VERSION 5.8 ;
BUSBITCHARS "[]" ;
DIVIDERCHAR "/" ;
MANUFACTURINGGRID 0.05 ;

UNITS
    DATABASE MICRONS 1000 ;
END UNITS

SITE CoreSite
    CLASS CORE ;
    SIZE 5.400 BY 64.800 ;
END CoreSite

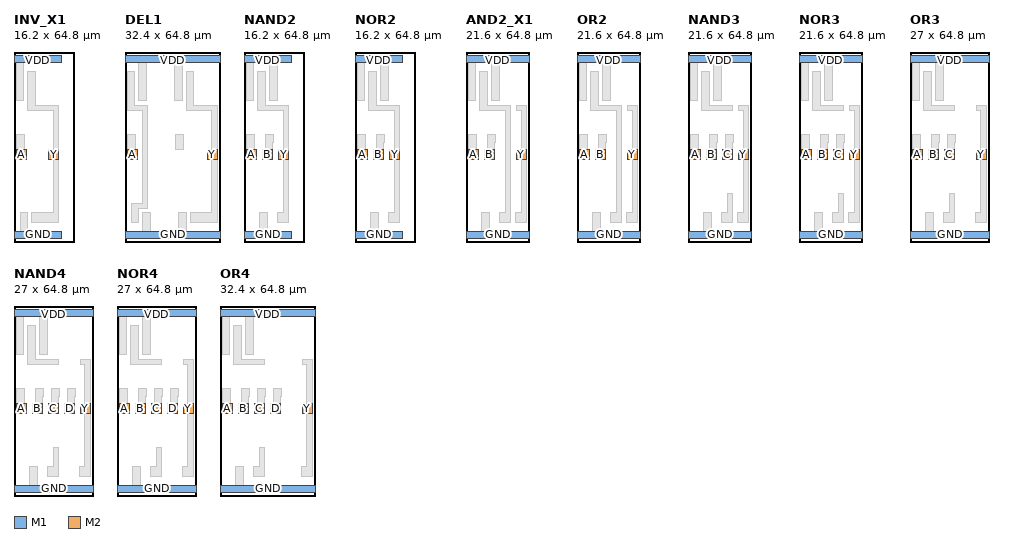
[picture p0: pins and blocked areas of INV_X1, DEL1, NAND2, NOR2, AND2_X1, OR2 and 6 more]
MACRO INV_X1
    CLASS CORE ;
    FOREIGN INV_X1 0.0 0.0 ;
    ORIGIN 0.0 0.0 ;
    SIZE 16.200 BY 64.800 ;
    SITE CoreSite ;

    PIN GND
        DIRECTION INOUT ;
        USE GROUND ;
        PORT
            LAYER M1 ;
                RECT 0.000 1.100 16.200 3.700 ;
        END
    END GND

    PIN VDD
        DIRECTION INOUT ;
        USE POWER ;
        PORT
            LAYER M1 ;
                RECT 0.000 61.100 16.200 63.700 ;
        END
    END VDD

    PIN A
        DIRECTION INPUT ;
        USE SIGNAL ;
        PORT
            LAYER M2 ;
                RECT 1.000 28.000 4.400 31.400 ;
        END
    END A

    PIN Y
        DIRECTION OUTPUT ;
        USE SIGNAL ;
        PORT
            LAYER M2 ;
                RECT 11.800 28.000 15.200 31.400 ;
        END
    END Y

    OBS
        LAYER M1 ;
            POLYGON 2.100 3.700  2.100 9.900  4.700 9.900  4.700 3.700 ;
            POLYGON 1.000 28.000  1.000 36.500  3.600 36.500  3.600 31.400  4.400 31.400  4.400 28.000 ;
            POLYGON 6.100 6.500  6.100 9.900  13.400 9.900  13.400 28.000  11.800 28.000  11.800 31.400  13.400 31.400  13.400 44.900  4.700 44.900  4.700 58.300  7.300 58.300  7.300 46.700  15.200 46.700  15.200 6.500 ;
            POLYGON 0.700 48.100  0.700 61.100  3.300 61.100  3.300 48.100 ;
    END

END INV_X1
MACRO DEL1
    CLASS CORE ;
    FOREIGN DEL1 0.0 0.0 ;
    ORIGIN 0.0 0.0 ;
    SIZE 32.400 BY 64.800 ;
    SITE CoreSite ;

    PIN GND
        DIRECTION INOUT ;
        USE GROUND ;
        PORT
            LAYER M1 ;
                RECT 0.000 1.100 32.400 3.700 ;
        END
    END GND

    PIN VDD
        DIRECTION INOUT ;
        USE POWER ;
        PORT
            LAYER M1 ;
                RECT 0.000 61.100 32.400 63.700 ;
        END
    END VDD

    PIN A
        DIRECTION INPUT ;
        USE SIGNAL ;
        PORT
            LAYER M2 ;
                RECT 1.000 28.000 4.400 31.400 ;
        END
    END A

    PIN Y
        DIRECTION OUTPUT ;
        USE SIGNAL ;
        PORT
            LAYER M2 ;
                RECT 28.000 28.000 31.400 31.400 ;
        END
    END Y

    OBS
        LAYER M1 ;
            POLYGON 6.100 3.700  6.100 9.900  8.700 9.900  8.700 3.700 ;
            POLYGON 18.300 3.700  18.300 9.900  20.900 9.900  20.900 3.700 ;
            POLYGON 1.000 28.000  1.000 36.500  3.600 36.500  3.600 31.400  4.400 31.400  4.400 28.000 ;
            POLYGON 17.200 31.400  17.200 36.500  19.800 36.500  19.800 31.400 ;
            POLYGON 2.100 6.500  2.100 13.300  6.000 13.300  6.000 44.900  0.700 44.900  0.700 58.300  3.300 58.300  3.300 46.700  7.800 46.700  7.800 11.500  4.700 11.500  4.700 6.500 ;
            POLYGON 22.300 6.500  22.300 9.900  29.600 9.900  29.600 28.000  28.000 28.000  28.000 31.400  29.600 31.400  29.600 44.900  20.900 44.900  20.900 58.300  23.500 58.300  23.500 46.700  31.400 46.700  31.400 6.500 ;
            POLYGON 4.700 48.100  4.700 61.100  7.300 61.100  7.300 48.100 ;
            POLYGON 16.900 48.100  16.900 61.100  19.500 61.100  19.500 48.100 ;
    END

END DEL1
MACRO NAND2
    CLASS CORE ;
    FOREIGN NAND2 0.0 0.0 ;
    ORIGIN 0.0 0.0 ;
    SIZE 16.200 BY 64.800 ;
    SITE CoreSite ;

    PIN GND
        DIRECTION INOUT ;
        USE GROUND ;
        PORT
            LAYER M1 ;
                RECT 0.000 1.100 16.200 3.700 ;
        END
    END GND

    PIN VDD
        DIRECTION INOUT ;
        USE POWER ;
        PORT
            LAYER M1 ;
                RECT 0.000 61.100 16.200 63.700 ;
        END
    END VDD

    PIN A
        DIRECTION INPUT ;
        USE SIGNAL ;
        PORT
            LAYER M2 ;
                RECT 1.000 28.000 4.400 31.400 ;
        END
    END A

    PIN B
        DIRECTION INPUT ;
        USE SIGNAL ;
        PORT
            LAYER M2 ;
                RECT 6.400 28.000 9.800 31.400 ;
        END
    END B

    PIN Y
        DIRECTION OUTPUT ;
        USE SIGNAL ;
        PORT
            LAYER M2 ;
                RECT 11.800 28.000 15.200 31.400 ;
        END
    END Y

    OBS
        LAYER M1 ;
            POLYGON 5.300 3.700  5.300 9.900  7.900 9.900  7.900 3.700 ;
            POLYGON 1.000 28.000  1.000 36.500  3.600 36.500  3.600 31.400  4.400 31.400  4.400 28.000 ;
            POLYGON 6.400 28.000  6.400 31.400  7.500 31.400  7.500 36.500  10.100 36.500  10.100 33.900  9.800 33.900  9.800 28.000 ;
            POLYGON 11.500 6.500  11.500 9.900  13.400 9.900  13.400 28.000  11.800 28.000  11.800 31.400  13.400 31.400  13.400 44.900  4.700 44.900  4.700 58.300  7.300 58.300  7.300 46.700  15.200 46.700  15.200 6.500 ;
            POLYGON 0.700 48.100  0.700 61.100  3.300 61.100  3.300 48.100 ;
            POLYGON 8.700 48.100  8.700 61.100  11.300 61.100  11.300 48.100 ;
    END

END NAND2
MACRO NOR2
    CLASS CORE ;
    FOREIGN NOR2 0.0 0.0 ;
    ORIGIN 0.0 0.0 ;
    SIZE 16.200 BY 64.800 ;
    SITE CoreSite ;

    PIN GND
        DIRECTION INOUT ;
        USE GROUND ;
        PORT
            LAYER M1 ;
                RECT 0.000 1.100 16.200 3.700 ;
        END
    END GND

    PIN VDD
        DIRECTION INOUT ;
        USE POWER ;
        PORT
            LAYER M1 ;
                RECT 0.000 61.100 16.200 63.700 ;
        END
    END VDD

    PIN A
        DIRECTION INPUT ;
        USE SIGNAL ;
        PORT
            LAYER M2 ;
                RECT 1.000 28.000 4.400 31.400 ;
        END
    END A

    PIN B
        DIRECTION INPUT ;
        USE SIGNAL ;
        PORT
            LAYER M2 ;
                RECT 6.400 28.000 9.800 31.400 ;
        END
    END B

    PIN Y
        DIRECTION OUTPUT ;
        USE SIGNAL ;
        PORT
            LAYER M2 ;
                RECT 11.800 28.000 15.200 31.400 ;
        END
    END Y

    OBS
        LAYER M1 ;
            POLYGON 5.300 3.700  5.300 9.900  7.900 9.900  7.900 3.700 ;
            POLYGON 1.000 28.000  1.000 36.500  3.600 36.500  3.600 31.400  4.400 31.400  4.400 28.000 ;
            POLYGON 6.400 28.000  6.400 31.400  7.500 31.400  7.500 36.500  10.100 36.500  10.100 33.900  9.800 33.900  9.800 28.000 ;
            POLYGON 11.500 6.500  11.500 9.900  13.400 9.900  13.400 28.000  11.800 28.000  11.800 31.400  13.400 31.400  13.400 44.900  4.700 44.900  4.700 58.300  7.300 58.300  7.300 46.700  15.200 46.700  15.200 6.500 ;
            POLYGON 0.700 48.100  0.700 61.100  3.300 61.100  3.300 48.100 ;
            POLYGON 8.700 48.100  8.700 61.100  11.300 61.100  11.300 48.100 ;
    END

END NOR2
MACRO AND2_X1
    CLASS CORE ;
    FOREIGN AND2_X1 0.0 0.0 ;
    ORIGIN 0.0 0.0 ;
    SIZE 21.600 BY 64.800 ;
    SITE CoreSite ;

    PIN GND
        DIRECTION INOUT ;
        USE GROUND ;
        PORT
            LAYER M1 ;
                RECT 0.000 1.100 21.600 3.700 ;
        END
    END GND

    PIN VDD
        DIRECTION INOUT ;
        USE POWER ;
        PORT
            LAYER M1 ;
                RECT 0.000 61.100 21.600 63.700 ;
        END
    END VDD

    PIN A
        DIRECTION INPUT ;
        USE SIGNAL ;
        PORT
            LAYER M2 ;
                RECT 1.000 28.000 4.400 31.400 ;
        END
    END A

    PIN B
        DIRECTION INPUT ;
        USE SIGNAL ;
        PORT
            LAYER M2 ;
                RECT 6.400 28.000 9.800 31.400 ;
        END
    END B

    PIN Y
        DIRECTION OUTPUT ;
        USE SIGNAL ;
        PORT
            LAYER M2 ;
                RECT 17.200 28.000 20.600 31.400 ;
        END
    END Y

    OBS
        LAYER M1 ;
            POLYGON 5.300 3.700  5.300 9.900  7.900 9.900  7.900 3.700 ;
            POLYGON 1.000 28.000  1.000 36.500  3.600 36.500  3.600 31.400  4.400 31.400  4.400 28.000 ;
            POLYGON 6.400 28.000  6.400 31.400  7.500 31.400  7.500 36.500  10.100 36.500  10.100 33.900  9.800 33.900  9.800 28.000 ;
            POLYGON 16.900 6.500  16.900 9.900  18.800 9.900  18.800 28.000  17.200 28.000  17.200 31.400  18.800 31.400  18.800 44.900  17.200 44.900  17.200 46.700  20.600 46.700  20.600 6.500 ;
            POLYGON 11.500 6.500  11.500 9.900  13.400 9.900  13.400 44.900  4.700 44.900  4.700 58.300  7.300 58.300  7.300 46.700  15.200 46.700  15.200 6.500 ;
            POLYGON 0.700 48.100  0.700 61.100  3.300 61.100  3.300 48.100 ;
            POLYGON 8.700 48.100  8.700 61.100  11.300 61.100  11.300 48.100 ;
    END

END AND2_X1
MACRO OR2
    CLASS CORE ;
    FOREIGN OR2 0.0 0.0 ;
    ORIGIN 0.0 0.0 ;
    SIZE 21.600 BY 64.800 ;
    SITE CoreSite ;

    PIN GND
        DIRECTION INOUT ;
        USE GROUND ;
        PORT
            LAYER M1 ;
                RECT 0.000 1.100 21.600 3.700 ;
        END
    END GND

    PIN VDD
        DIRECTION INOUT ;
        USE POWER ;
        PORT
            LAYER M1 ;
                RECT 0.000 61.100 21.600 63.700 ;
        END
    END VDD

    PIN A
        DIRECTION INPUT ;
        USE SIGNAL ;
        PORT
            LAYER M2 ;
                RECT 1.000 28.000 4.400 31.400 ;
        END
    END A

    PIN B
        DIRECTION INPUT ;
        USE SIGNAL ;
        PORT
            LAYER M2 ;
                RECT 6.400 28.000 9.800 31.400 ;
        END
    END B

    PIN Y
        DIRECTION OUTPUT ;
        USE SIGNAL ;
        PORT
            LAYER M2 ;
                RECT 17.200 28.000 20.600 31.400 ;
        END
    END Y

    OBS
        LAYER M1 ;
            POLYGON 5.300 3.700  5.300 9.900  7.900 9.900  7.900 3.700 ;
            POLYGON 1.000 28.000  1.000 36.500  3.600 36.500  3.600 31.400  4.400 31.400  4.400 28.000 ;
            POLYGON 6.400 28.000  6.400 31.400  7.500 31.400  7.500 36.500  10.100 36.500  10.100 33.900  9.800 33.900  9.800 28.000 ;
            POLYGON 16.900 6.500  16.900 9.900  18.800 9.900  18.800 28.000  17.200 28.000  17.200 31.400  18.800 31.400  18.800 44.900  17.200 44.900  17.200 46.700  20.600 46.700  20.600 6.500 ;
            POLYGON 11.500 6.500  11.500 9.900  13.400 9.900  13.400 44.900  4.700 44.900  4.700 58.300  7.300 58.300  7.300 46.700  15.200 46.700  15.200 6.500 ;
            POLYGON 0.700 48.100  0.700 61.100  3.300 61.100  3.300 48.100 ;
            POLYGON 8.700 48.100  8.700 61.100  11.300 61.100  11.300 48.100 ;
    END

END OR2
MACRO NAND3
    CLASS CORE ;
    FOREIGN NAND3 0.0 0.0 ;
    ORIGIN 0.0 0.0 ;
    SIZE 21.600 BY 64.800 ;
    SITE CoreSite ;

    PIN GND
        DIRECTION INOUT ;
        USE GROUND ;
        PORT
            LAYER M1 ;
                RECT 0.000 1.100 21.600 3.700 ;
        END
    END GND

    PIN VDD
        DIRECTION INOUT ;
        USE POWER ;
        PORT
            LAYER M1 ;
                RECT 0.000 61.100 21.600 63.700 ;
        END
    END VDD

    PIN A
        DIRECTION INPUT ;
        USE SIGNAL ;
        PORT
            LAYER M2 ;
                RECT 1.000 28.000 4.400 31.400 ;
        END
    END A

    PIN B
        DIRECTION INPUT ;
        USE SIGNAL ;
        PORT
            LAYER M2 ;
                RECT 6.400 28.000 9.800 31.400 ;
        END
    END B

    PIN C
        DIRECTION INPUT ;
        USE SIGNAL ;
        PORT
            LAYER M2 ;
                RECT 11.800 28.000 15.200 31.400 ;
        END
    END C

    PIN Y
        DIRECTION OUTPUT ;
        USE SIGNAL ;
        PORT
            LAYER M2 ;
                RECT 17.200 28.000 20.600 31.400 ;
        END
    END Y

    OBS
        LAYER M1 ;
            POLYGON 5.300 3.700  5.300 9.900  7.900 9.900  7.900 3.700 ;
            POLYGON 11.500 6.500  11.500 9.900  13.400 9.900  13.400 16.700  15.200 16.700  15.200 6.500 ;
            POLYGON 1.000 28.000  1.000 36.500  3.600 36.500  3.600 31.400  4.400 31.400  4.400 28.000 ;
            POLYGON 6.400 28.000  6.400 31.400  7.500 31.400  7.500 36.500  10.100 36.500  10.100 33.900  9.800 33.900  9.800 28.000 ;
            POLYGON 11.800 28.000  11.800 31.400  12.900 31.400  12.900 36.500  15.500 36.500  15.500 33.900  15.200 33.900  15.200 28.000 ;
            POLYGON 16.900 6.500  16.900 9.900  18.800 9.900  18.800 28.000  17.200 28.000  17.200 31.400  18.800 31.400  18.800 44.900  17.200 44.900  17.200 46.700  20.600 46.700  20.600 6.500 ;
            POLYGON 4.700 44.900  4.700 58.300  7.300 58.300  7.300 46.700  15.200 46.700  15.200 44.900 ;
            POLYGON 0.700 48.100  0.700 61.100  3.300 61.100  3.300 48.100 ;
            POLYGON 8.700 48.100  8.700 61.100  11.300 61.100  11.300 48.100 ;
    END

END NAND3
MACRO NOR3
    CLASS CORE ;
    FOREIGN NOR3 0.0 0.0 ;
    ORIGIN 0.0 0.0 ;
    SIZE 21.600 BY 64.800 ;
    SITE CoreSite ;

    PIN GND
        DIRECTION INOUT ;
        USE GROUND ;
        PORT
            LAYER M1 ;
                RECT 0.000 1.100 21.600 3.700 ;
        END
    END GND

    PIN VDD
        DIRECTION INOUT ;
        USE POWER ;
        PORT
            LAYER M1 ;
                RECT 0.000 61.100 21.600 63.700 ;
        END
    END VDD

    PIN A
        DIRECTION INPUT ;
        USE SIGNAL ;
        PORT
            LAYER M2 ;
                RECT 1.000 28.000 4.400 31.400 ;
        END
    END A

    PIN B
        DIRECTION INPUT ;
        USE SIGNAL ;
        PORT
            LAYER M2 ;
                RECT 6.400 28.000 9.800 31.400 ;
        END
    END B

    PIN C
        DIRECTION INPUT ;
        USE SIGNAL ;
        PORT
            LAYER M2 ;
                RECT 11.800 28.000 15.200 31.400 ;
        END
    END C

    PIN Y
        DIRECTION OUTPUT ;
        USE SIGNAL ;
        PORT
            LAYER M2 ;
                RECT 17.200 28.000 20.600 31.400 ;
        END
    END Y

    OBS
        LAYER M1 ;
            POLYGON 5.300 3.700  5.300 9.900  7.900 9.900  7.900 3.700 ;
            POLYGON 11.500 6.500  11.500 9.900  13.400 9.900  13.400 16.700  15.200 16.700  15.200 6.500 ;
            POLYGON 1.000 28.000  1.000 36.500  3.600 36.500  3.600 31.400  4.400 31.400  4.400 28.000 ;
            POLYGON 6.400 28.000  6.400 31.400  7.500 31.400  7.500 36.500  10.100 36.500  10.100 33.900  9.800 33.900  9.800 28.000 ;
            POLYGON 11.800 28.000  11.800 31.400  12.900 31.400  12.900 36.500  15.500 36.500  15.500 33.900  15.200 33.900  15.200 28.000 ;
            POLYGON 16.900 6.500  16.900 9.900  18.800 9.900  18.800 28.000  17.200 28.000  17.200 31.400  18.800 31.400  18.800 44.900  17.200 44.900  17.200 46.700  20.600 46.700  20.600 6.500 ;
            POLYGON 4.700 44.900  4.700 58.300  7.300 58.300  7.300 46.700  15.200 46.700  15.200 44.900 ;
            POLYGON 0.700 48.100  0.700 61.100  3.300 61.100  3.300 48.100 ;
            POLYGON 8.700 48.100  8.700 61.100  11.300 61.100  11.300 48.100 ;
    END

END NOR3
MACRO OR3
    CLASS CORE ;
    FOREIGN OR3 0.0 0.0 ;
    ORIGIN 0.0 0.0 ;
    SIZE 27.000 BY 64.800 ;
    SITE CoreSite ;

    PIN GND
        DIRECTION INOUT ;
        USE GROUND ;
        PORT
            LAYER M1 ;
                RECT 0.000 1.100 27.000 3.700 ;
        END
    END GND

    PIN VDD
        DIRECTION INOUT ;
        USE POWER ;
        PORT
            LAYER M1 ;
                RECT 0.000 61.100 27.000 63.700 ;
        END
    END VDD

    PIN A
        DIRECTION INPUT ;
        USE SIGNAL ;
        PORT
            LAYER M2 ;
                RECT 1.000 28.000 4.400 31.400 ;
        END
    END A

    PIN B
        DIRECTION INPUT ;
        USE SIGNAL ;
        PORT
            LAYER M2 ;
                RECT 6.400 28.000 9.800 31.400 ;
        END
    END B

    PIN C
        DIRECTION INPUT ;
        USE SIGNAL ;
        PORT
            LAYER M2 ;
                RECT 11.800 28.000 15.200 31.400 ;
        END
    END C

    PIN Y
        DIRECTION OUTPUT ;
        USE SIGNAL ;
        PORT
            LAYER M2 ;
                RECT 22.600 28.000 26.000 31.400 ;
        END
    END Y

    OBS
        LAYER M1 ;
            POLYGON 5.300 3.700  5.300 9.900  7.900 9.900  7.900 3.700 ;
            POLYGON 11.500 6.500  11.500 9.900  13.400 9.900  13.400 16.700  15.200 16.700  15.200 6.500 ;
            POLYGON 1.000 28.000  1.000 36.500  3.600 36.500  3.600 31.400  4.400 31.400  4.400 28.000 ;
            POLYGON 6.400 28.000  6.400 31.400  7.500 31.400  7.500 36.500  10.100 36.500  10.100 33.900  9.800 33.900  9.800 28.000 ;
            POLYGON 11.800 28.000  11.800 31.400  12.900 31.400  12.900 36.500  15.500 36.500  15.500 33.900  15.200 33.900  15.200 28.000 ;
            POLYGON 22.300 6.500  22.300 9.900  24.200 9.900  24.200 28.000  22.600 28.000  22.600 31.400  24.200 31.400  24.200 44.900  22.600 44.900  22.600 46.700  26.000 46.700  26.000 6.500 ;
            POLYGON 4.700 44.900  4.700 58.300  7.300 58.300  7.300 46.700  15.200 46.700  15.200 44.900 ;
            POLYGON 0.700 48.100  0.700 61.100  3.300 61.100  3.300 48.100 ;
            POLYGON 8.700 48.100  8.700 61.100  11.300 61.100  11.300 48.100 ;
    END

END OR3
MACRO NAND4
    CLASS CORE ;
    FOREIGN NAND4 0.0 0.0 ;
    ORIGIN 0.0 0.0 ;
    SIZE 27.000 BY 64.800 ;
    SITE CoreSite ;

    PIN GND
        DIRECTION INOUT ;
        USE GROUND ;
        PORT
            LAYER M1 ;
                RECT 0.000 1.100 27.000 3.700 ;
        END
    END GND

    PIN VDD
        DIRECTION INOUT ;
        USE POWER ;
        PORT
            LAYER M1 ;
                RECT 0.000 61.100 27.000 63.700 ;
        END
    END VDD

    PIN A
        DIRECTION INPUT ;
        USE SIGNAL ;
        PORT
            LAYER M2 ;
                RECT 1.000 28.000 4.400 31.400 ;
        END
    END A

    PIN B
        DIRECTION INPUT ;
        USE SIGNAL ;
        PORT
            LAYER M2 ;
                RECT 6.400 28.000 9.800 31.400 ;
        END
    END B

    PIN C
        DIRECTION INPUT ;
        USE SIGNAL ;
        PORT
            LAYER M2 ;
                RECT 11.800 28.000 15.200 31.400 ;
        END
    END C

    PIN D
        DIRECTION INPUT ;
        USE SIGNAL ;
        PORT
            LAYER M2 ;
                RECT 17.200 28.000 20.600 31.400 ;
        END
    END D

    PIN Y
        DIRECTION OUTPUT ;
        USE SIGNAL ;
        PORT
            LAYER M2 ;
                RECT 22.600 28.000 26.000 31.400 ;
        END
    END Y

    OBS
        LAYER M1 ;
            POLYGON 5.300 3.700  5.300 9.900  7.900 9.900  7.900 3.700 ;
            POLYGON 11.500 6.500  11.500 9.900  13.400 9.900  13.400 16.700  15.200 16.700  15.200 6.500 ;
            POLYGON 1.000 28.000  1.000 36.500  3.600 36.500  3.600 31.400  4.400 31.400  4.400 28.000 ;
            POLYGON 6.400 28.000  6.400 31.400  7.500 31.400  7.500 36.500  10.100 36.500  10.100 33.900  9.800 33.900  9.800 28.000 ;
            POLYGON 11.800 28.000  11.800 31.400  12.900 31.400  12.900 36.500  15.500 36.500  15.500 33.900  15.200 33.900  15.200 28.000 ;
            POLYGON 17.200 28.000  17.200 31.400  18.300 31.400  18.300 36.500  20.900 36.500  20.900 33.900  20.600 33.900  20.600 28.000 ;
            POLYGON 22.300 6.500  22.300 9.900  24.200 9.900  24.200 28.000  22.600 28.000  22.600 31.400  24.200 31.400  24.200 44.900  22.600 44.900  22.600 46.700  26.000 46.700  26.000 6.500 ;
            POLYGON 4.700 44.900  4.700 58.300  7.300 58.300  7.300 46.700  15.200 46.700  15.200 44.900 ;
            POLYGON 0.700 48.100  0.700 61.100  3.300 61.100  3.300 48.100 ;
            POLYGON 8.700 48.100  8.700 61.100  11.300 61.100  11.300 48.100 ;
    END

END NAND4
MACRO NOR4
    CLASS CORE ;
    FOREIGN NOR4 0.0 0.0 ;
    ORIGIN 0.0 0.0 ;
    SIZE 27.000 BY 64.800 ;
    SITE CoreSite ;

    PIN GND
        DIRECTION INOUT ;
        USE GROUND ;
        PORT
            LAYER M1 ;
                RECT 0.000 1.100 27.000 3.700 ;
        END
    END GND

    PIN VDD
        DIRECTION INOUT ;
        USE POWER ;
        PORT
            LAYER M1 ;
                RECT 0.000 61.100 27.000 63.700 ;
        END
    END VDD

    PIN A
        DIRECTION INPUT ;
        USE SIGNAL ;
        PORT
            LAYER M2 ;
                RECT 1.000 28.000 4.400 31.400 ;
        END
    END A

    PIN B
        DIRECTION INPUT ;
        USE SIGNAL ;
        PORT
            LAYER M2 ;
                RECT 6.400 28.000 9.800 31.400 ;
        END
    END B

    PIN C
        DIRECTION INPUT ;
        USE SIGNAL ;
        PORT
            LAYER M2 ;
                RECT 11.800 28.000 15.200 31.400 ;
        END
    END C

    PIN D
        DIRECTION INPUT ;
        USE SIGNAL ;
        PORT
            LAYER M2 ;
                RECT 17.200 28.000 20.600 31.400 ;
        END
    END D

    PIN Y
        DIRECTION OUTPUT ;
        USE SIGNAL ;
        PORT
            LAYER M2 ;
                RECT 22.600 28.000 26.000 31.400 ;
        END
    END Y

    OBS
        LAYER M1 ;
            POLYGON 5.300 3.700  5.300 9.900  7.900 9.900  7.900 3.700 ;
            POLYGON 11.500 6.500  11.500 9.900  13.400 9.900  13.400 16.700  15.200 16.700  15.200 6.500 ;
            POLYGON 1.000 28.000  1.000 36.500  3.600 36.500  3.600 31.400  4.400 31.400  4.400 28.000 ;
            POLYGON 6.400 28.000  6.400 31.400  7.500 31.400  7.500 36.500  10.100 36.500  10.100 33.900  9.800 33.900  9.800 28.000 ;
            POLYGON 11.800 28.000  11.800 31.400  12.900 31.400  12.900 36.500  15.500 36.500  15.500 33.900  15.200 33.900  15.200 28.000 ;
            POLYGON 17.200 28.000  17.200 31.400  18.300 31.400  18.300 36.500  20.900 36.500  20.900 33.900  20.600 33.900  20.600 28.000 ;
            POLYGON 22.300 6.500  22.300 9.900  24.200 9.900  24.200 28.000  22.600 28.000  22.600 31.400  24.200 31.400  24.200 44.900  22.600 44.900  22.600 46.700  26.000 46.700  26.000 6.500 ;
            POLYGON 4.700 44.900  4.700 58.300  7.300 58.300  7.300 46.700  15.200 46.700  15.200 44.900 ;
            POLYGON 0.700 48.100  0.700 61.100  3.300 61.100  3.300 48.100 ;
            POLYGON 8.700 48.100  8.700 61.100  11.300 61.100  11.300 48.100 ;
    END

END NOR4
MACRO OR4
    CLASS CORE ;
    FOREIGN OR4 0.0 0.0 ;
    ORIGIN 0.0 0.0 ;
    SIZE 32.400 BY 64.800 ;
    SITE CoreSite ;

    PIN GND
        DIRECTION INOUT ;
        USE GROUND ;
        PORT
            LAYER M1 ;
                RECT 0.000 1.100 32.400 3.700 ;
        END
    END GND

    PIN VDD
        DIRECTION INOUT ;
        USE POWER ;
        PORT
            LAYER M1 ;
                RECT 0.000 61.100 32.400 63.700 ;
        END
    END VDD

    PIN A
        DIRECTION INPUT ;
        USE SIGNAL ;
        PORT
            LAYER M2 ;
                RECT 1.000 28.000 4.400 31.400 ;
        END
    END A

    PIN B
        DIRECTION INPUT ;
        USE SIGNAL ;
        PORT
            LAYER M2 ;
                RECT 6.400 28.000 9.800 31.400 ;
        END
    END B

    PIN C
        DIRECTION INPUT ;
        USE SIGNAL ;
        PORT
            LAYER M2 ;
                RECT 11.800 28.000 15.200 31.400 ;
        END
    END C

    PIN D
        DIRECTION INPUT ;
        USE SIGNAL ;
        PORT
            LAYER M2 ;
                RECT 17.200 28.000 20.600 31.400 ;
        END
    END D

    PIN Y
        DIRECTION OUTPUT ;
        USE SIGNAL ;
        PORT
            LAYER M2 ;
                RECT 28.000 28.000 31.400 31.400 ;
        END
    END Y

    OBS
        LAYER M1 ;
            POLYGON 5.300 3.700  5.300 9.900  7.900 9.900  7.900 3.700 ;
            POLYGON 11.500 6.500  11.500 9.900  13.400 9.900  13.400 16.700  15.200 16.700  15.200 6.500 ;
            POLYGON 1.000 28.000  1.000 36.500  3.600 36.500  3.600 31.400  4.400 31.400  4.400 28.000 ;
            POLYGON 6.400 28.000  6.400 31.400  7.500 31.400  7.500 36.500  10.100 36.500  10.100 33.900  9.800 33.900  9.800 28.000 ;
            POLYGON 11.800 28.000  11.800 31.400  12.900 31.400  12.900 36.500  15.500 36.500  15.500 33.900  15.200 33.900  15.200 28.000 ;
            POLYGON 17.200 28.000  17.200 31.400  18.300 31.400  18.300 36.500  20.900 36.500  20.900 33.900  20.600 33.900  20.600 28.000 ;
            POLYGON 27.700 6.500  27.700 9.900  29.600 9.900  29.600 28.000  28.000 28.000  28.000 31.400  29.600 31.400  29.600 44.900  28.000 44.900  28.000 46.700  31.400 46.700  31.400 6.500 ;
            POLYGON 4.700 44.900  4.700 58.300  7.300 58.300  7.300 46.700  15.200 46.700  15.200 44.900 ;
            POLYGON 0.700 48.100  0.700 61.100  3.300 61.100  3.300 48.100 ;
            POLYGON 8.700 48.100  8.700 61.100  11.300 61.100  11.300 48.100 ;
    END

END OR4
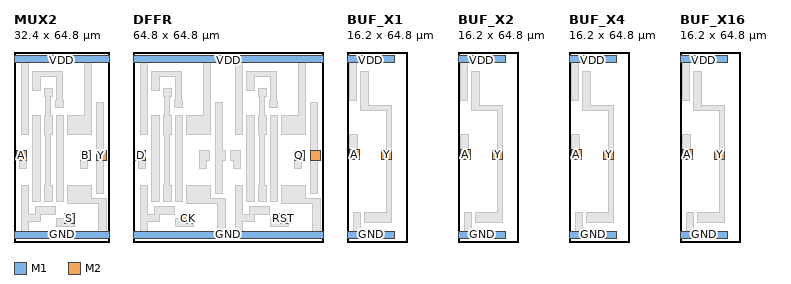
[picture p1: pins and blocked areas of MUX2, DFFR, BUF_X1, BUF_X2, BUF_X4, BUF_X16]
MACRO MUX2
    CLASS CORE ;
    FOREIGN MUX2 0.0 0.0 ;
    ORIGIN 0.0 0.0 ;
    SIZE 32.400 BY 64.800 ;
    SITE CoreSite ;

    PIN GND
        DIRECTION INOUT ;
        USE GROUND ;
        PORT
            LAYER M1 ;
                RECT 0.000 1.100 32.400 3.700 ;
        END
    END GND

    PIN VDD
        DIRECTION INOUT ;
        USE POWER ;
        PORT
            LAYER M1 ;
                RECT 0.000 61.100 32.400 63.700 ;
        END
    END VDD

    PIN S
        DIRECTION INPUT ;
        USE SIGNAL ;
        PORT
            LAYER M2 ;
                RECT 17.200 6.300 20.600 9.700 ;
        END
    END S

    PIN A
        DIRECTION INPUT ;
        USE SIGNAL ;
        PORT
            LAYER M2 ;
                RECT 1.000 27.900 4.400 31.300 ;
        END
    END A

    PIN B
        DIRECTION INPUT ;
        USE SIGNAL ;
        PORT
            LAYER M2 ;
                RECT 22.600 27.900 26.000 31.300 ;
        END
    END B

    PIN Y
        DIRECTION OUTPUT ;
        USE SIGNAL ;
        PORT
            LAYER M2 ;
                RECT 28.000 27.900 31.400 31.300 ;
        END
    END Y

    OBS
        LAYER M1 ;
            POLYGON 14.400 5.300  14.400 7.900  17.200 7.900  17.200 9.700  20.600 9.700  20.600 5.300 ;
            POLYGON 2.400 3.700  2.400 19.300  5.000 19.300  5.000 9.500  7.200 9.500  7.200 12.100  14.200 12.100  14.200 9.500  9.000 9.500  9.000 6.900  5.000 6.900  5.000 3.700 ;
            POLYGON 28.800 3.700  28.800 13.200  18.400 13.200  18.400 19.300  26.500 19.300  26.500 15.000  31.400 15.000  31.400 3.700 ;
            POLYGON 1.800 25.100  1.800 27.900  1.000 27.900  1.000 31.300  4.400 31.300  4.400 25.100 ;
            POLYGON 22.600 25.100  22.600 31.300  26.000 31.300  26.000 27.900  25.200 27.900  25.200 25.100 ;
            POLYGON 6.400 13.700  6.400 43.300  9.000 43.300  9.000 13.700 ;
            POLYGON 14.400 13.700  14.400 43.300  17.000 43.300  17.000 13.700 ;
            POLYGON 28.000 16.600  28.000 47.600  30.600 47.600  30.600 31.300  31.400 31.300  31.400 27.900  30.600 27.900  30.600 16.600 ;
            POLYGON 10.400 13.700  10.400 19.300  10.800 19.300  10.800 36.700  10.400 36.700  10.400 43.300  10.800 43.300  10.800 49.600  10.400 49.600  10.400 52.200  13.000 52.200  13.000 49.600  12.600 49.600  12.600 43.300  13.000 43.300  13.000 36.700  12.600 36.700  12.600 19.300  13.000 19.300  13.000 13.700 ;
            POLYGON 14.200 45.800  14.200 48.400  14.600 48.400  14.600 56.400  9.000 56.400  9.000 51.600  6.400 51.600  6.400 58.200  16.400 58.200  16.400 48.400  16.800 48.400  16.800 45.800 ;
            POLYGON 2.400 36.700  2.400 61.100  5.000 61.100  5.000 36.700 ;
            POLYGON 18.400 36.700  18.400 43.300  23.900 43.300  23.900 61.100  26.500 61.100  26.500 36.700 ;
    END

END MUX2
MACRO DFFR
    CLASS CORE ;
    FOREIGN DFFR 0.0 0.0 ;
    ORIGIN 0.0 0.0 ;
    SIZE 64.800 BY 64.800 ;
    SITE CoreSite ;

    PIN GND
        DIRECTION INOUT ;
        USE GROUND ;
        PORT
            LAYER M1 ;
                RECT 0.000 1.100 64.800 3.700 ;
        END
    END GND

    PIN VDD
        DIRECTION INOUT ;
        USE POWER ;
        PORT
            LAYER M1 ;
                RECT 0.000 61.100 64.800 63.700 ;
        END
    END VDD

    PIN CK
        DIRECTION INPUT ;
        USE CLOCK ;
        PORT
            LAYER M2 ;
                RECT 17.200 6.300 20.600 9.700 ;
        END
    END CK

    PIN RST
        DIRECTION INPUT ;
        USE SIGNAL ;
        PORT
            LAYER M2 ;
                RECT 49.600 6.300 53.000 9.700 ;
        END
    END RST

    PIN D
        DIRECTION INPUT ;
        USE SIGNAL ;
        PORT
            LAYER M2 ;
                RECT 1.000 27.900 4.400 31.300 ;
        END
    END D

    PIN Q
        DIRECTION OUTPUT ;
        USE SIGNAL ;
        PORT
            LAYER M2 ;
                RECT 55.000 27.900 58.400 31.300 ;
        END
    END Q

    PIN QB
        DIRECTION OUTPUT ;
        USE SIGNAL ;
        PORT
            LAYER M2 ;
                RECT 60.400 27.900 63.800 31.300 ;
        END
    END QB

    OBS
        LAYER M1 ;
            POLYGON 14.400 5.300  14.400 7.900  17.200 7.900  17.200 9.700  20.600 9.700  20.600 5.300 ;
            POLYGON 46.800 5.300  46.800 7.900  49.600 7.900  49.600 9.700  53.000 9.700  53.000 5.300 ;
            POLYGON 2.400 3.700  2.400 19.300  5.000 19.300  5.000 9.500  7.200 9.500  7.200 12.100  14.200 12.100  14.200 9.500  9.000 9.500  9.000 6.900  5.000 6.900  5.000 3.700 ;
            POLYGON 28.800 3.700  28.800 13.200  18.400 13.200  18.400 19.300  26.500 19.300  26.500 15.000  31.400 15.000  31.400 3.700 ;
            POLYGON 34.800 3.700  34.800 19.300  37.400 19.300  37.400 9.500  39.600 9.500  39.600 12.100  46.600 12.100  46.600 9.500  41.400 9.500  41.400 6.900  37.400 6.900  37.400 3.700 ;
            POLYGON 61.200 3.700  61.200 13.200  50.800 13.200  50.800 19.300  58.900 19.300  58.900 15.000  63.800 15.000  63.800 3.700 ;
            POLYGON 1.800 25.100  1.800 27.900  1.000 27.900  1.000 31.300  4.400 31.300  4.400 25.100 ;
            POLYGON 22.600 25.100  22.600 31.300  26.000 31.300  26.000 27.900  25.200 27.900  25.200 25.100 ;
            POLYGON 34.200 25.100  34.200 27.900  33.400 27.900  33.400 31.300  36.800 31.300  36.800 25.100 ;
            POLYGON 55.000 25.100  55.000 31.300  58.400 31.300  58.400 27.900  57.600 27.900  57.600 25.100 ;
            POLYGON 6.400 13.700  6.400 43.300  9.000 43.300  9.000 13.700 ;
            POLYGON 14.400 13.700  14.400 43.300  17.000 43.300  17.000 13.700 ;
            POLYGON 38.800 13.700  38.800 43.300  41.400 43.300  41.400 13.700 ;
            POLYGON 46.800 13.700  46.800 43.300  49.400 43.300  49.400 13.700 ;
            POLYGON 28.000 16.600  28.000 47.600  30.600 47.600  30.600 31.300  31.400 31.300  31.400 27.900  30.600 27.900  30.600 16.600 ;
            POLYGON 60.400 16.600  60.400 47.600  63.000 47.600  63.000 31.300  63.800 31.300  63.800 27.900  63.000 27.900  63.000 16.600 ;
            POLYGON 10.400 13.700  10.400 19.300  10.800 19.300  10.800 36.700  10.400 36.700  10.400 43.300  10.800 43.300  10.800 49.600  10.400 49.600  10.400 52.200  13.000 52.200  13.000 49.600  12.600 49.600  12.600 43.300  13.000 43.300  13.000 36.700  12.600 36.700  12.600 19.300  13.000 19.300  13.000 13.700 ;
            POLYGON 42.800 13.700  42.800 19.300  43.200 19.300  43.200 36.700  42.800 36.700  42.800 43.300  43.200 43.300  43.200 49.600  42.800 49.600  42.800 52.200  45.400 52.200  45.400 49.600  45.000 49.600  45.000 43.300  45.400 43.300  45.400 36.700  45.000 36.700  45.000 19.300  45.400 19.300  45.400 13.700 ;
            POLYGON 14.200 45.800  14.200 48.400  14.600 48.400  14.600 56.400  9.000 56.400  9.000 51.600  6.400 51.600  6.400 58.200  16.400 58.200  16.400 48.400  16.800 48.400  16.800 45.800 ;
            POLYGON 46.600 45.800  46.600 48.400  47.000 48.400  47.000 56.400  41.400 56.400  41.400 51.600  38.800 51.600  38.800 58.200  48.800 58.200  48.800 48.400  49.200 48.400  49.200 45.800 ;
            POLYGON 2.400 36.700  2.400 61.100  5.000 61.100  5.000 36.700 ;
            POLYGON 18.400 36.700  18.400 43.300  23.900 43.300  23.900 61.100  26.500 61.100  26.500 36.700 ;
            POLYGON 34.800 36.700  34.800 61.100  37.400 61.100  37.400 36.700 ;
            POLYGON 50.800 36.700  50.800 43.300  56.300 43.300  56.300 61.100  58.900 61.100  58.900 36.700 ;
    END

END DFFR
MACRO BUF_X1
    CLASS CORE ;
    FOREIGN BUF_X1 0.0 0.0 ;
    ORIGIN 0.0 0.0 ;
    SIZE 16.200 BY 64.800 ;
    SITE CoreSite ;

    PIN GND
        DIRECTION INOUT ;
        USE GROUND ;
        PORT
            LAYER M1 ;
                RECT 0.000 1.100 16.200 3.700 ;
        END
    END GND

    PIN VDD
        DIRECTION INOUT ;
        USE POWER ;
        PORT
            LAYER M1 ;
                RECT 0.000 61.100 16.200 63.700 ;
        END
    END VDD

    PIN A
        DIRECTION INPUT ;
        USE SIGNAL ;
        PORT
            LAYER M2 ;
                RECT 1.000 28.000 4.400 31.400 ;
        END
    END A

    PIN Y
        DIRECTION OUTPUT ;
        USE SIGNAL ;
        PORT
            LAYER M2 ;
                RECT 11.800 28.000 15.200 31.400 ;
        END
    END Y

    OBS
        LAYER M1 ;
            POLYGON 2.100 3.700  2.100 9.900  4.700 9.900  4.700 3.700 ;
            POLYGON 1.000 28.000  1.000 36.500  3.600 36.500  3.600 31.400  4.400 31.400  4.400 28.000 ;
            POLYGON 6.100 6.500  6.100 9.900  13.400 9.900  13.400 28.000  11.800 28.000  11.800 31.400  13.400 31.400  13.400 44.900  4.700 44.900  4.700 58.300  7.300 58.300  7.300 46.700  15.200 46.700  15.200 6.500 ;
            POLYGON 0.700 48.100  0.700 61.100  3.300 61.100  3.300 48.100 ;
    END

END BUF_X1
MACRO BUF_X2
    CLASS CORE ;
    FOREIGN BUF_X1 0.0 0.0 ;
    ORIGIN 0.0 0.0 ;
    SIZE 16.200 BY 64.800 ;
    SITE CoreSite ;

    PIN GND
        DIRECTION INOUT ;
        USE GROUND ;
        PORT
            LAYER M1 ;
                RECT 0.000 1.100 16.200 3.700 ;
        END
    END GND

    PIN VDD
        DIRECTION INOUT ;
        USE POWER ;
        PORT
            LAYER M1 ;
                RECT 0.000 61.100 16.200 63.700 ;
        END
    END VDD

    PIN A
        DIRECTION INPUT ;
        USE SIGNAL ;
        PORT
            LAYER M2 ;
                RECT 1.000 28.000 4.400 31.400 ;
        END
    END A

    PIN Y
        DIRECTION OUTPUT ;
        USE SIGNAL ;
        PORT
            LAYER M2 ;
                RECT 11.800 28.000 15.200 31.400 ;
        END
    END Y

    OBS
        LAYER M1 ;
            POLYGON 2.100 3.700  2.100 9.900  4.700 9.900  4.700 3.700 ;
            POLYGON 1.000 28.000  1.000 36.500  3.600 36.500  3.600 31.400  4.400 31.400  4.400 28.000 ;
            POLYGON 6.100 6.500  6.100 9.900  13.400 9.900  13.400 28.000  11.800 28.000  11.800 31.400  13.400 31.400  13.400 44.900  4.700 44.900  4.700 58.300  7.300 58.300  7.300 46.700  15.200 46.700  15.200 6.500 ;
            POLYGON 0.700 48.100  0.700 61.100  3.300 61.100  3.300 48.100 ;
    END

END BUF_X2
MACRO BUF_X4
    CLASS CORE ;
    FOREIGN BUF_X1 0.0 0.0 ;
    ORIGIN 0.0 0.0 ;
    SIZE 16.200 BY 64.800 ;
    SITE CoreSite ;

    PIN GND
        DIRECTION INOUT ;
        USE GROUND ;
        PORT
            LAYER M1 ;
                RECT 0.000 1.100 16.200 3.700 ;
        END
    END GND

    PIN VDD
        DIRECTION INOUT ;
        USE POWER ;
        PORT
            LAYER M1 ;
                RECT 0.000 61.100 16.200 63.700 ;
        END
    END VDD

    PIN A
        DIRECTION INPUT ;
        USE SIGNAL ;
        PORT
            LAYER M2 ;
                RECT 1.000 28.000 4.400 31.400 ;
        END
    END A

    PIN Y
        DIRECTION OUTPUT ;
        USE SIGNAL ;
        PORT
            LAYER M2 ;
                RECT 11.800 28.000 15.200 31.400 ;
        END
    END Y

    OBS
        LAYER M1 ;
            POLYGON 2.100 3.700  2.100 9.900  4.700 9.900  4.700 3.700 ;
            POLYGON 1.000 28.000  1.000 36.500  3.600 36.500  3.600 31.400  4.400 31.400  4.400 28.000 ;
            POLYGON 6.100 6.500  6.100 9.900  13.400 9.900  13.400 28.000  11.800 28.000  11.800 31.400  13.400 31.400  13.400 44.900  4.700 44.900  4.700 58.300  7.300 58.300  7.300 46.700  15.200 46.700  15.200 6.500 ;
            POLYGON 0.700 48.100  0.700 61.100  3.300 61.100  3.300 48.100 ;
    END

END BUF_X4
MACRO BUF_X16
    CLASS CORE ;
    FOREIGN BUF_X1 0.0 0.0 ;
    ORIGIN 0.0 0.0 ;
    SIZE 16.200 BY 64.800 ;
    SITE CoreSite ;

    PIN GND
        DIRECTION INOUT ;
        USE GROUND ;
        PORT
            LAYER M1 ;
                RECT 0.000 1.100 16.200 3.700 ;
        END
    END GND

    PIN VDD
        DIRECTION INOUT ;
        USE POWER ;
        PORT
            LAYER M1 ;
                RECT 0.000 61.100 16.200 63.700 ;
        END
    END VDD

    PIN A
        DIRECTION INPUT ;
        USE SIGNAL ;
        PORT
            LAYER M2 ;
                RECT 1.000 28.000 4.400 31.400 ;
        END
    END A

    PIN Y
        DIRECTION OUTPUT ;
        USE SIGNAL ;
        PORT
            LAYER M2 ;
                RECT 11.800 28.000 15.200 31.400 ;
        END
    END Y

    OBS
        LAYER M1 ;
            POLYGON 2.100 3.700  2.100 9.900  4.700 9.900  4.700 3.700 ;
            POLYGON 1.000 28.000  1.000 36.500  3.600 36.500  3.600 31.400  4.400 31.400  4.400 28.000 ;
            POLYGON 6.100 6.500  6.100 9.900  13.400 9.900  13.400 28.000  11.800 28.000  11.800 31.400  13.400 31.400  13.400 44.900  4.700 44.900  4.700 58.300  7.300 58.300  7.300 46.700  15.200 46.700  15.200 6.500 ;
            POLYGON 0.700 48.100  0.700 61.100  3.300 61.100  3.300 48.100 ;
    END

END BUF_X16
END LIBRARY
